One B-rep face of a CAD part: STEP entity #17180.
In plain terms, the planar face has unit normal (0, 0, 1).
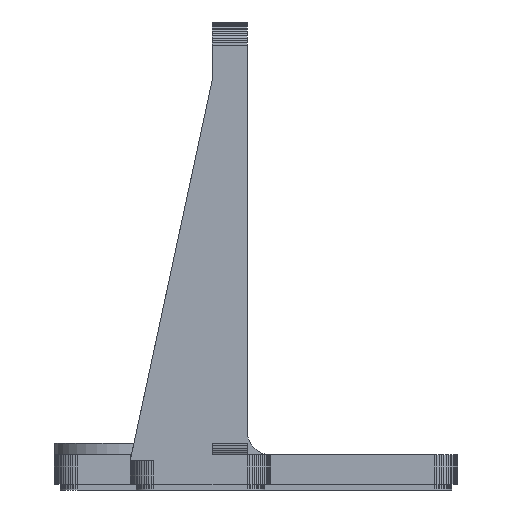
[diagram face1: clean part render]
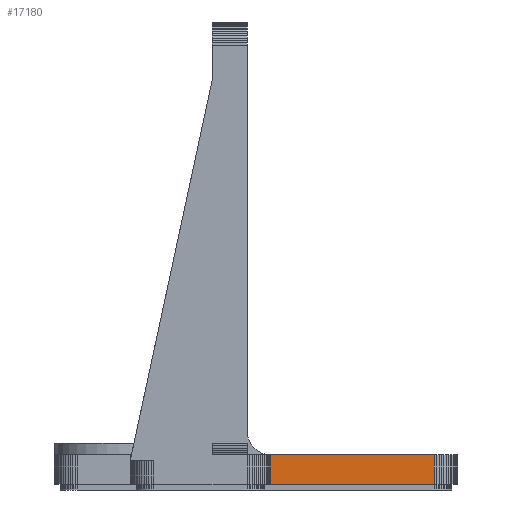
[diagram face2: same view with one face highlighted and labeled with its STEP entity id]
Its self-contained STEP definition (entity closure, numbers rounded to 3 decimals):
#90 = PLANE('',#91);
#91 = AXIS2_PLACEMENT_3D('',#92,#93,#94);
#92 = CARTESIAN_POINT('',(61.25,128.05,-29.25));
#93 = DIRECTION('',(0.,-1.,0.));
#94 = DIRECTION('',(1.,0.,0.));
#144 = PLANE('',#145);
#145 = AXIS2_PLACEMENT_3D('',#146,#147,#148);
#146 = CARTESIAN_POINT('',(61.25,130.55,-29.25));
#147 = DIRECTION('',(0.,-1.,0.));
#148 = DIRECTION('',(1.,0.,0.));
#1453 = VERTEX_POINT('',#1454);
#1454 = CARTESIAN_POINT('',(72.5,130.55,1.));
#1468 = PLANE('',#1469);
#1469 = AXIS2_PLACEMENT_3D('',#1470,#1471,#1472);
#1470 = CARTESIAN_POINT('',(72.709,130.55,0.989));
#1471 = DIRECTION('',(-0.052,0.,
    -0.999));
#1472 = DIRECTION('',(-0.999,0.,
    0.052));
#1480 = EDGE_CURVE('',#1453,#1481,#1483,.T.);
#1481 = VERTEX_POINT('',#1482);
#1482 = CARTESIAN_POINT('',(58.5,130.55,1.));
#1483 = SURFACE_CURVE('',#1484,(#1488,#1495),.PCURVE_S1.);
#1484 = LINE('',#1485,#1486);
#1485 = CARTESIAN_POINT('',(72.5,130.55,1.));
#1486 = VECTOR('',#1487,1.);
#1487 = DIRECTION('',(-1.,0.,0.));
#1488 = PCURVE('',#144,#1489);
#1489 = DEFINITIONAL_REPRESENTATION('',(#1490),#1494);
#1490 = LINE('',#1491,#1492);
#1491 = CARTESIAN_POINT('',(11.25,30.25));
#1492 = VECTOR('',#1493,1.);
#1493 = DIRECTION('',(-1.,0.));
#1494 = ( GEOMETRIC_REPRESENTATION_CONTEXT(2) 
PARAMETRIC_REPRESENTATION_CONTEXT() REPRESENTATION_CONTEXT('2D SPACE',''
  ) );
#1495 = PCURVE('',#1496,#1501);
#1496 = PLANE('',#1497);
#1497 = AXIS2_PLACEMENT_3D('',#1498,#1499,#1500);
#1498 = CARTESIAN_POINT('',(72.5,130.55,1.));
#1499 = DIRECTION('',(0.,0.,-1.));
#1500 = DIRECTION('',(-1.,0.,0.));
#1501 = DEFINITIONAL_REPRESENTATION('',(#1502),#1506);
#1502 = LINE('',#1503,#1504);
#1503 = CARTESIAN_POINT('',(0.,-0.));
#1504 = VECTOR('',#1505,1.);
#1505 = DIRECTION('',(1.,0.));
#1506 = ( GEOMETRIC_REPRESENTATION_CONTEXT(2) 
PARAMETRIC_REPRESENTATION_CONTEXT() REPRESENTATION_CONTEXT('2D SPACE',''
  ) );
#5619 = VERTEX_POINT('',#5620);
#5620 = CARTESIAN_POINT('',(72.5,128.05,1.));
#5641 = EDGE_CURVE('',#5619,#5642,#5644,.T.);
#5642 = VERTEX_POINT('',#5643);
#5643 = CARTESIAN_POINT('',(58.,128.05,1.));
#5644 = SURFACE_CURVE('',#5645,(#5649,#5656),.PCURVE_S1.);
#5645 = LINE('',#5646,#5647);
#5646 = CARTESIAN_POINT('',(72.5,128.05,1.));
#5647 = VECTOR('',#5648,1.);
#5648 = DIRECTION('',(-1.,0.,0.));
#5649 = PCURVE('',#90,#5650);
#5650 = DEFINITIONAL_REPRESENTATION('',(#5651),#5655);
#5651 = LINE('',#5652,#5653);
#5652 = CARTESIAN_POINT('',(11.25,30.25));
#5653 = VECTOR('',#5654,1.);
#5654 = DIRECTION('',(-1.,0.));
#5655 = ( GEOMETRIC_REPRESENTATION_CONTEXT(2) 
PARAMETRIC_REPRESENTATION_CONTEXT() REPRESENTATION_CONTEXT('2D SPACE',''
  ) );
#5656 = PCURVE('',#1496,#5657);
#5657 = DEFINITIONAL_REPRESENTATION('',(#5658),#5662);
#5658 = LINE('',#5659,#5660);
#5659 = CARTESIAN_POINT('',(0.,-2.5));
#5660 = VECTOR('',#5661,1.);
#5661 = DIRECTION('',(1.,0.));
#5662 = ( GEOMETRIC_REPRESENTATION_CONTEXT(2) 
PARAMETRIC_REPRESENTATION_CONTEXT() REPRESENTATION_CONTEXT('2D SPACE',''
  ) );
#5680 = PLANE('',#5681);
#5681 = AXIS2_PLACEMENT_3D('',#5682,#5683,#5684);
#5682 = CARTESIAN_POINT('',(58.,130.55,-21.));
#5683 = DIRECTION('',(-1.,0.,0.));
#5684 = DIRECTION('',(0.,0.,1.));
#17169 = PLANE('',#17170);
#17170 = AXIS2_PLACEMENT_3D('',#17171,#17172,#17173);
#17171 = CARTESIAN_POINT('',(56.5,130.55,0.9));
#17172 = DIRECTION('',(0.,1.,0.));
#17173 = DIRECTION('',(1.,0.,0.));
#17180 = ADVANCED_FACE('',(#17181),#1496,.F.);
#17181 = FACE_BOUND('',#17182,.F.);
#17182 = EDGE_LOOP('',(#17183,#17184,#17205,#17206,#17227));
#17183 = ORIENTED_EDGE('',*,*,#1480,.F.);
#17184 = ORIENTED_EDGE('',*,*,#17185,.T.);
#17185 = EDGE_CURVE('',#1453,#5619,#17186,.T.);
#17186 = SURFACE_CURVE('',#17187,(#17191,#17198),.PCURVE_S1.);
#17187 = LINE('',#17188,#17189);
#17188 = CARTESIAN_POINT('',(72.5,130.55,1.));
#17189 = VECTOR('',#17190,1.);
#17190 = DIRECTION('',(0.,-1.,0.));
#17191 = PCURVE('',#1496,#17192);
#17192 = DEFINITIONAL_REPRESENTATION('',(#17193),#17197);
#17193 = LINE('',#17194,#17195);
#17194 = CARTESIAN_POINT('',(0.,-0.));
#17195 = VECTOR('',#17196,1.);
#17196 = DIRECTION('',(0.,-1.));
#17197 = ( GEOMETRIC_REPRESENTATION_CONTEXT(2) 
PARAMETRIC_REPRESENTATION_CONTEXT() REPRESENTATION_CONTEXT('2D SPACE',''
  ) );
#17198 = PCURVE('',#1468,#17199);
#17199 = DEFINITIONAL_REPRESENTATION('',(#17200),#17204);
#17200 = LINE('',#17201,#17202);
#17201 = CARTESIAN_POINT('',(0.209,0.));
#17202 = VECTOR('',#17203,1.);
#17203 = DIRECTION('',(0.,-1.));
#17204 = ( GEOMETRIC_REPRESENTATION_CONTEXT(2) 
PARAMETRIC_REPRESENTATION_CONTEXT() REPRESENTATION_CONTEXT('2D SPACE',''
  ) );
#17205 = ORIENTED_EDGE('',*,*,#5641,.T.);
#17206 = ORIENTED_EDGE('',*,*,#17207,.T.);
#17207 = EDGE_CURVE('',#5642,#17208,#17210,.T.);
#17208 = VERTEX_POINT('',#17209);
#17209 = CARTESIAN_POINT('',(58.,130.55,1.));
#17210 = SURFACE_CURVE('',#17211,(#17215,#17221),.PCURVE_S1.);
#17211 = LINE('',#17212,#17213);
#17212 = CARTESIAN_POINT('',(58.,130.55,1.));
#17213 = VECTOR('',#17214,1.);
#17214 = DIRECTION('',(0.,1.,0.));
#17215 = PCURVE('',#1496,#17216);
#17216 = DEFINITIONAL_REPRESENTATION('',(#17217),#17220);
#17217 = B_SPLINE_CURVE_WITH_KNOTS('',1,(#17218,#17219),.UNSPECIFIED.,
  .F.,.F.,(2,2),(-2.5,0.),.PIECEWISE_BEZIER_KNOTS.);
#17218 = CARTESIAN_POINT('',(14.5,-2.5));
#17219 = CARTESIAN_POINT('',(14.5,0.));
#17220 = ( GEOMETRIC_REPRESENTATION_CONTEXT(2) 
PARAMETRIC_REPRESENTATION_CONTEXT() REPRESENTATION_CONTEXT('2D SPACE',''
  ) );
#17221 = PCURVE('',#5680,#17222);
#17222 = DEFINITIONAL_REPRESENTATION('',(#17223),#17226);
#17223 = B_SPLINE_CURVE_WITH_KNOTS('',1,(#17224,#17225),.UNSPECIFIED.,
  .F.,.F.,(2,2),(-2.5,0.),.PIECEWISE_BEZIER_KNOTS.);
#17224 = CARTESIAN_POINT('',(22.,-2.5));
#17225 = CARTESIAN_POINT('',(22.,0.));
#17226 = ( GEOMETRIC_REPRESENTATION_CONTEXT(2) 
PARAMETRIC_REPRESENTATION_CONTEXT() REPRESENTATION_CONTEXT('2D SPACE',''
  ) );
#17227 = ORIENTED_EDGE('',*,*,#17228,.F.);
#17228 = EDGE_CURVE('',#1481,#17208,#17229,.T.);
#17229 = SURFACE_CURVE('',#17230,(#17234,#17241),.PCURVE_S1.);
#17230 = LINE('',#17231,#17232);
#17231 = CARTESIAN_POINT('',(72.5,130.55,1.));
#17232 = VECTOR('',#17233,1.);
#17233 = DIRECTION('',(-1.,0.,0.));
#17234 = PCURVE('',#1496,#17235);
#17235 = DEFINITIONAL_REPRESENTATION('',(#17236),#17240);
#17236 = LINE('',#17237,#17238);
#17237 = CARTESIAN_POINT('',(0.,-0.));
#17238 = VECTOR('',#17239,1.);
#17239 = DIRECTION('',(1.,0.));
#17240 = ( GEOMETRIC_REPRESENTATION_CONTEXT(2) 
PARAMETRIC_REPRESENTATION_CONTEXT() REPRESENTATION_CONTEXT('2D SPACE',''
  ) );
#17241 = PCURVE('',#17169,#17242);
#17242 = DEFINITIONAL_REPRESENTATION('',(#17243),#17247);
#17243 = LINE('',#17244,#17245);
#17244 = CARTESIAN_POINT('',(16.,-0.1));
#17245 = VECTOR('',#17246,1.);
#17246 = DIRECTION('',(-1.,0.));
#17247 = ( GEOMETRIC_REPRESENTATION_CONTEXT(2) 
PARAMETRIC_REPRESENTATION_CONTEXT() REPRESENTATION_CONTEXT('2D SPACE',''
  ) );
